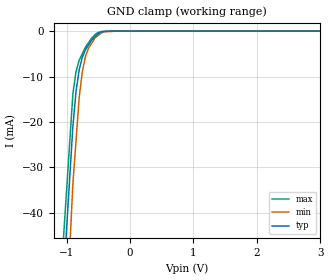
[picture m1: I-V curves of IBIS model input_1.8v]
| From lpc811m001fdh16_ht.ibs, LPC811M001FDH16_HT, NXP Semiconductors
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[Model] input_1.8v
Model_type Input
Vinl = 540.000mV
Vinh = 1.26000V
C_comp 909.000fF 904.000fF 914.000fF
| variable typ   min   max
[Voltage Range] 1.80000V 1.65000V 1.95000V
[POWER Clamp Reference] 1.80000V 1.65000V 1.95000V
[GND Clamp Reference] 0.00000V 0.00000V 0.00000V
[Temperature Range]   25   105   -40
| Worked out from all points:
|   GND clamp passes 1 mA (typ) near -0.53 V on its own axis
[GND Clamp]
-1.8V     -226.1mA   -292.9mA   -207.1mA
-900mV    -20.98mA   -33.67mA   -13.8mA
-850mV    -13.28mA   -24.09mA   -8.911mA
-800mV    -8.483mA   -14.52mA   -6.412mA
-750mV    -5.729mA   -8.869mA   -4.946mA
-700mV    -4.056mA   -5.491mA   -3.479mA
-650mV    -2.988mA   -3.674mA   -2.487mA
-550mV    -1.226mA   -1.484mA   -758.6uA
-500mV    -532.9uA   -938.4uA   -295.9uA
-400mV    -46.91uA   -141uA     -71.69uA
-200mV    -8.97uA    -9.8uA     -21.03uA
3.6V      0A         0A         0A
[POWER Clamp]
-1.8V     0A         0A         0A
3.6V      0A         0A         0A
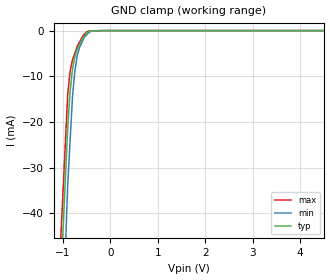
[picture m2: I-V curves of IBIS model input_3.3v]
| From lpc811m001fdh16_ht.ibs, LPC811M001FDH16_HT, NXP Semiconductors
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[Model] input_3.3v
Model_type Input
Vinl = 990.000mV
Vinh = 2.31000V
C_comp 909.000fF 904.000fF 914.000fF
| variable typ   min   max
[Voltage Range] 3.30000V 3.00000V 3.60000V
[POWER Clamp Reference] 3.30000V 3.00000V 3.60000V
[GND Clamp Reference] 0.00000V 0.00000V 0.00000V
[Temperature Range]   25   105   -40
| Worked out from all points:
|   GND clamp passes 1 mA (typ) near -0.53 V on its own axis
[GND Clamp]
-3.3V     -567.9mA   -725mA     -529.3mA
-900mV    -20.98mA   -33.67mA   -13.8mA
-850mV    -13.28mA   -24.09mA   -8.911mA
-800mV    -8.483mA   -14.52mA   -6.412mA
-750mV    -5.729mA   -8.869mA   -4.946mA
-700mV    -4.056mA   -5.491mA   -3.479mA
-650mV    -2.988mA   -3.674mA   -2.487mA
-550mV    -1.226mA   -1.484mA   -758.6uA
-500mV    -532.9uA   -938.4uA   -295.9uA
-400mV    -46.91uA   -141uA     -71.69uA
-200mV    -8.97uA    -9.8uA     -21.03uA
6.6V      0A         0A         0A
[POWER Clamp]
-3.3V     0A         0A         0A
6.6V      0A         0A         0A
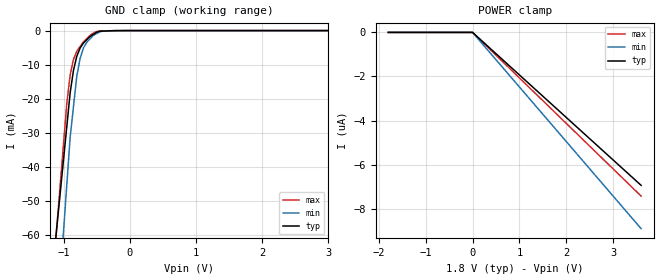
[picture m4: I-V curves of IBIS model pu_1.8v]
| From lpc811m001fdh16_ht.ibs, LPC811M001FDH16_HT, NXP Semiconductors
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[Model] pu_1.8v
Model_type Input
Vinl = 540.000mV
Vinh = 1.26000V
C_comp 909.000fF 904.000fF 914.000fF
| variable typ   min   max
[Voltage Range] 1.80000V 1.65000V 1.95000V
[POWER Clamp Reference] 1.80000V 1.65000V 1.95000V
[GND Clamp Reference] 0.00000V 0.00000V 0.00000V
[Temperature Range]   25   105   -40
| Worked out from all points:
|   GND clamp passes 1 mA (typ) near -0.54 V on its own axis
[GND Clamp]
-1.8V     -194.6mA   -279.4mA   -224.6mA
-950mV    -28.04mA   -45.07mA   -21.27mA
-900mV    -18.25mA   -31.28mA   -13mA
-850mV    -11.68mA   -22.35mA   -8.425mA
-800mV    -7.541mA   -13.41mA   -6.076mA
-750mV    -5.144mA   -8.205mA   -4.681mA
-700mV    -3.664mA   -5.125mA   -3.287mA
-650mV    -2.706mA   -3.458mA   -2.35mA
-550mV    -1.121mA   -1.408mA   -717.3uA
-400mV    -147.2uA   -139.2uA   -68.5uA
-200mV    -21.15uA   -18.17uA   -21.06uA
3.6V      0A         0A         0A
[POWER Clamp]
-1.8V     0A         0A         0A
0V        0A         0A         0A
3.6V      -6.941uA   -8.906uA   -7.427uA
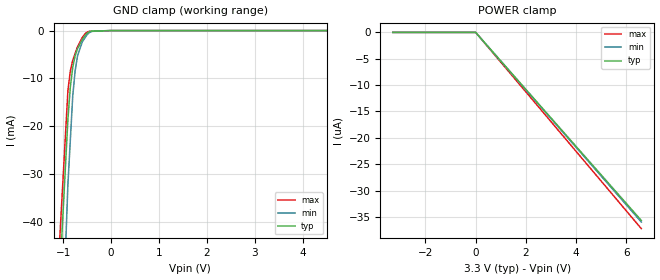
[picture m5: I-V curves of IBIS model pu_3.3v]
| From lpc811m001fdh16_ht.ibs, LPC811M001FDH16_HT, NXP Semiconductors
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[Model] pu_3.3v
Model_type Input
Vinl = 990.000mV
Vinh = 2.31000V
C_comp 909.000fF 904.000fF 914.000fF
| variable typ   min   max
[Voltage Range] 3.30000V 3.00000V 3.60000V
[POWER Clamp Reference] 3.30000V 3.00000V 3.60000V
[GND Clamp Reference] 0.00000V 0.00000V 0.00000V
[Temperature Range]   25   105   -40
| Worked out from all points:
|   GND clamp passes 1 mA (typ) near -0.54 V on its own axis
[GND Clamp]
-3.3V     -481.7mA   -686.3mA   -449mA
-900mV    -18.53mA   -32.17mA   -12.56mA
-850mV    -11.85mA   -22.98mA   -8.473mA
-800mV    -7.74mA    -13.78mA   -6.254mA
-750mV    -5.325mA   -8.465mA   -4.829mA
-700mV    -3.812mA   -5.309mA   -3.403mA
-600mV    -1.827mA   -2.349mA   -1.457mA
-550mV    -1.183mA   -1.595mA   -748.6uA
-500mV    -537.7uA   -841.1uA   -319uA
-400mV    -100.7uA   -173uA     -124uA
0V        0A         0A         0A
6.6V      0A         0A         0A
[POWER Clamp]
-3.3V     0A         0A         0A
0V        0A         0A         0A
6.6V      -35.67uA   -35.96uA   -37.22uA
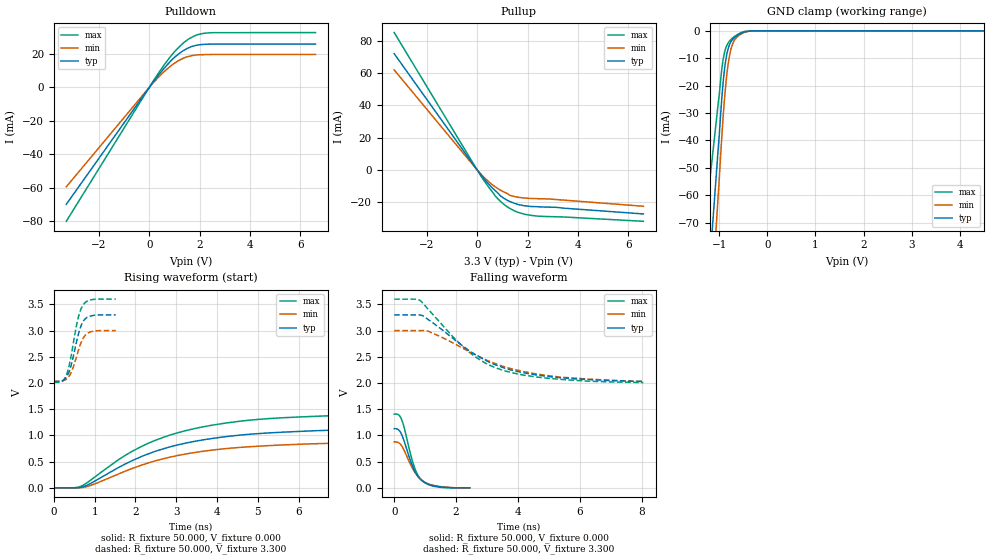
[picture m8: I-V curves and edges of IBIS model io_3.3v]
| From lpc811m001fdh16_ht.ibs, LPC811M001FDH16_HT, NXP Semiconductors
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[Model]   io_3.3v
Model_type I/O
Vinl=7.500E-01
Vinh=2.310E+00
Vref=0.000E+00
Rref=1.000E+06
Cref=2.000E-11
Vmeas=1.650E+00
C_comp   6.740E-13   6.620E-13   6.860E-13
[Voltage Range]   3.300E+00   3.000E+00   3.600E+00
[POWER Clamp Reference]   3.300E+00   3.000E+00   3.600E+00
[GND Clamp Reference]   0.000E+00   0.000E+00   0.000E+00
[Pullup Reference]   3.300E+00   3.000E+00   3.600E+00
[Pulldown Reference]   0.000E+00   0.000E+00   0.000E+00
[Temperature Range]   25   105   -40
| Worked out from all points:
|   slope of the pulldown table from 0 to 0.495 V, typ, clamps not added: 51.1 ohm
|   slope of the pullup table from 0 to 0.495 V, typ, clamps not added: 52.8 ohm
|   GND clamp passes 1 mA (typ) near -0.56 V on its own axis
|   rising waveform, R_fixture 50.000, V_fixture 0.000: 20-80 % time 2.35ns typ, 2.39ns min, 2.3ns max; typ from 0 V to 1.13 V
|   falling waveform, R_fixture 50.000, V_fixture 0.000: 20-80 % time 446ps typ, 505ps min, 399ps max; typ from 1.13 V to 0 V
|   rising waveform, R_fixture 50.000, V_fixture 3.300: 20-80 % time 242ps typ, 251ps min, 237ps max; typ from 2.03 V to 3.3 V
|   falling waveform, R_fixture 50.000, V_fixture 3.300: 20-80 % time 2.09ns typ, 2.37ns min, 1.84ns max; typ from 3.3 V to 2.03 V
[GND Clamp]
-3.3V     -588.5mA   -700.7mA   -393.5mA
-1.02V    -42.37mA   -59.29mA   -26.07mA
-1V       -37.98mA   -53.93mA   -23.34mA
-960mV    -27.56mA   -42.13mA   -15.89mA
-920mV    -18.87mA   -31.47mA   -10.48mA
-880mV    -12.49mA   -22.52mA   -7.138mA
-820mV    -6.819mA   -12.68mA   -4.563mA
-760mV    -4.057mA   -6.887mA   -3.228mA
-700mV    -2.719mA   -3.87mA    -2.258mA
-560mV    -996.8uA   -1.297mA   -753.3uA
-280mV    0A         0A         0A
6.6V      0A         0A         0A
[POWER Clamp]
-3.3V     0A         0A         0A
6.6V      0A         0A         0A
[Pullup]
-3.3V     72.06mA    62.01mA    85.16mA
80mV      -1.647mA   -1.409mA   -2.034mA
400mV     -7.816mA   -6.431mA   -9.395mA
720mV     -12.83mA   -10.45mA   -16.17mA
920mV     -15.95mA   -12.45mA   -19.35mA
1.1V      -17.89mA   -13.87mA   -21.72mA
1.3V      -19.5mA    -15.64mA   -23.77mA
1.56V     -21.01mA   -16.65mA   -25.83mA
2.2V      -22.62mA   -17.62mA   -28.18mA
3.16V     -23.1mA    -18.29mA   -28.93mA
6.6V      -27.18mA   -22.42mA   -31.73mA
[Pulldown]
-3.3V     -69.88mA   -59.44mA   -80.02mA
160mV     3.31mA     2.772mA    3.836mA
580mV     11.24mA    9.263mA    13.18mA
840mV     15.57mA    12.61mA    18.32mA
1.04V     18.4mA     14.81mA    21.92mA
1.38V     22.17mA    17.55mA    26.83mA
1.58V     23.72mA    18.54mA    29mA
1.86V     25.05mA    19.3mA     31.09mA
2.26V     25.7mA     19.55mA    32.39mA
6.6V      25.81mA    19.62mA    32.68mA
[Rising Waveform]
R_fixture = 50.000
V_fixture = 0.000
V_fixture_min = 0.000
V_fixture_max = 0.000
|  time   V(typ)   V(min)   V(max)
0s        0V         0V         0V
660ps     9.804mV    3.652mV    29.06mV
920ps     91.74mV    50.39mV    156.8mV
1.62ns    401.8mV    275.4mV    554.5mV
2.16ns    601mV      435.3mV    793.7mV
2.86ns    783.9mV    587.4mV    1.009V
3.64ns    912.4mV    695.5mV    1.161V
4.54ns    1.004V     770.2mV    1.269V
5.5ns     1.057V     814.1mV    1.332V
9.16ns    1.13V      878mV      1.408V
[Falling Waveform]
R_fixture = 50.000
V_fixture = 0.000
V_fixture_min = 0.000
V_fixture_max = 0.000
|  time   V(typ)   V(min)   V(max)
0s        1.13V      878mV      1.408V
140ps     1.107V     862.2mV    1.393V
240ps     1.019V     803.4mV    1.304V
340ps     859.6mV    692.1mV    1.11V
620ps     378.3mV    343.5mV    452.4mV
740ps     244.3mV    237.9mV    270.6mV
880ps     144.9mV    151.8mV    152.8mV
1.1ns     69.19mV    76.27mV    66.24mV
1.36ns    28.86mV    37.81mV    21.61mV
2.44ns    0V         0V         0V
[Rising Waveform]
R_fixture = 50.000
V_fixture = 3.300
V_fixture_min = 3.000
V_fixture_max = 3.600
|  time   V(typ)   V(min)   V(max)
0s        2.03V      2.031V     2.01V
200ps     2.043V     2.037V     2.033V
320ps     2.124V     2.081V     2.175V
420ps     2.326V     2.193V     2.502V
580ps     2.863V     2.565V     3.185V
640ps     3.032V     2.711V     3.358V
720ps     3.176V     2.854V     3.492V
800ps     3.244V     2.934V     3.553V
920ps     3.281V     2.98V      3.588V
1.52ns    3.3V       3V         3.6V
[Falling Waveform]
R_fixture = 50.000
V_fixture = 3.300
V_fixture_min = 3.000
V_fixture_max = 3.600
|  time   V(typ)   V(min)   V(max)
0s        3.3V       3V         3.6V
820ps     3.299V     3V         3.582V
1.08ns    3.219V     2.994V     3.419V
1.92ns    2.842V     2.758V     2.868V
2.38ns    2.636V     2.614V     2.609V
2.94ns    2.438V     2.451V     2.383V
3.46ns    2.308V     2.329V     2.253V
4.16ns    2.198V     2.222V     2.154V
5.28ns    2.107V     2.12V      2.075V
8.06ns    2.03V      2.031V     2.01V
[Ramp]
dV/dt_r   6.7806E-01/2.3543E-09   5.2641E-01/2.3841E-09   8.4375E-01/2.2977E-09
dV/dt_f   7.6177E-01/2.0912E-09   5.8122E-01/2.3663E-09   9.5373E-01/1.8410E-09
R_load = 50
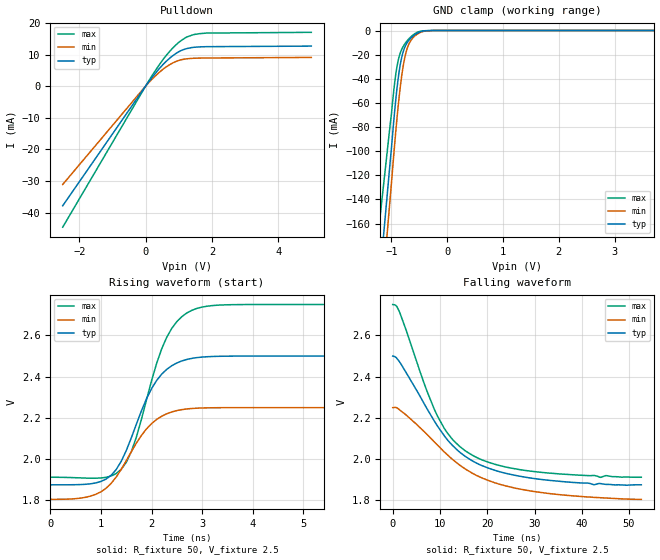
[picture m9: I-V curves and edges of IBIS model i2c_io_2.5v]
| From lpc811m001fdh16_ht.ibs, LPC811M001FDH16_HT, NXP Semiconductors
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[Model]   i2c_io_2.5v
Model_type I/O_open_drain
Vinl=7.500E-01
Vinh=1.750E+00
Vref=2.500E+00
Rref=1.000E+03
Cref=0.000E+00
Vmeas=1.250E+00
C_comp   1.060E-12   9.990E-13   1.120E-12
[Voltage Range]   2.500E+00   2.250E+00   2.750E+00
[POWER Clamp Reference]   2.500E+00   2.250E+00   2.750E+00
[GND Clamp Reference]   0.000E+00   0.000E+00   0.000E+00
[Pullup Reference]   2.500E+00   2.250E+00   2.750E+00
[Pulldown Reference]   0.000E+00   0.000E+00   0.000E+00
[Temperature Range]   25   105   -40
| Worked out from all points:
|   slope of the pulldown table from 0 to 0.375 V, typ, clamps not added: 74 ohm
|   GND clamp passes 1 mA (typ) near -0.48 V on its own axis
|   rising waveform, R_fixture 50, V_fixture 2.5: 20-80 % time 662ps typ, 716ps min, 623ps max; typ from 1.88 V to 2.5 V
|   falling waveform, R_fixture 50, V_fixture 2.5: 20-80 % time 12.3ns typ, 15.1ns min, 9.87ns max; typ from 2.5 V to 1.88 V
[GND Clamp]
-2.5V     -871.4mA   -953mA     -702mA
-1.02V    -107.3mA   -137.3mA   -76.75mA
-940mV    -65.71mA   -92.99mA   -42.42mA
-900mV    -47.69mA   -72.39mA   -29.64mA
-860mV    -33.38mA   -54.17mA   -21.27mA
-800mV    -19.22mA   -32.5mA    -14.12mA
-760mV    -13.76mA   -22.26mA   -11.09mA
-700mV    -8.816mA   -12.56mA   -7.482mA
-640mV    -5.775mA   -7.529mA   -4.759mA
-540mV    -2.236mA   -3.07mA    -1.531mA
-260mV    -4.949uA   -10.54uA   -1.512uA
5V        0A         0A         0A
[Pulldown]
-2.5V     -37.8mA    -31.08mA   -44.56mA
180mV     2.565mA    2.056mA    3.083mA
620mV     7.838mA    6.082mA    9.666mA
820mV     9.63mA     7.337mA    12.05mA
1.04V     11.1mA     8.257mA    14.16mA
1.24V     11.87mA    8.644mA    15.52mA
1.44V     12.27mA    8.811mA    16.26mA
1.84V     12.48mA    8.899mA    16.78mA
5V        12.66mA    9.081mA    17.01mA
[Rising Waveform]
R_fixture = 50
V_fixture = 2.5
V_fixture_min = 2.25
V_fixture_max = 2.75
0s        1.876V     1.805V     1.912V
900ps     1.885V     1.83V      1.908V
1.2ns     1.922V     1.882V     1.918V
1.4ns     1.989V     1.95V      1.951V
1.7ns     2.17V      2.078V     2.107V
2ns       2.342V     2.172V     2.381V
2.3ns     2.436V     2.22V      2.591V
2.5ns     2.467V     2.236V     2.667V
2.8ns     2.489V     2.246V     2.722V
7.6ns     2.5V       2.25V      2.75V
[Falling Waveform]
R_fixture = 50
V_fixture = 2.5
V_fixture_min = 2.25
V_fixture_max = 2.75
0s        2.5V       2.25V      2.75V
1.4ns     2.473V     2.241V     2.716V
6.7ns     2.267V     2.133V     2.364V
9.5ns     2.16V      2.068V     2.208V
12.3ns    2.075V     2.006V     2.106V
15.4ns    2.013V     1.952V     2.04V
20.4ns    1.955V     1.895V     1.984V
28.6ns    1.911V     1.848V     1.944V
42.6ns    1.876V     1.815V     1.921V
52.6ns    1.876V     1.805V     1.912V
[Ramp]
dV/dt_r   3.7455E-01/6.5770E-10   2.6675E-01/7.1020E-10   5.0254E-01/6.1810E-10
dV/dt_f   3.7455E-01/1.2195E-08   2.6675E-01/1.5100E-08   5.0254E-01/9.8059E-09
R_load = 50
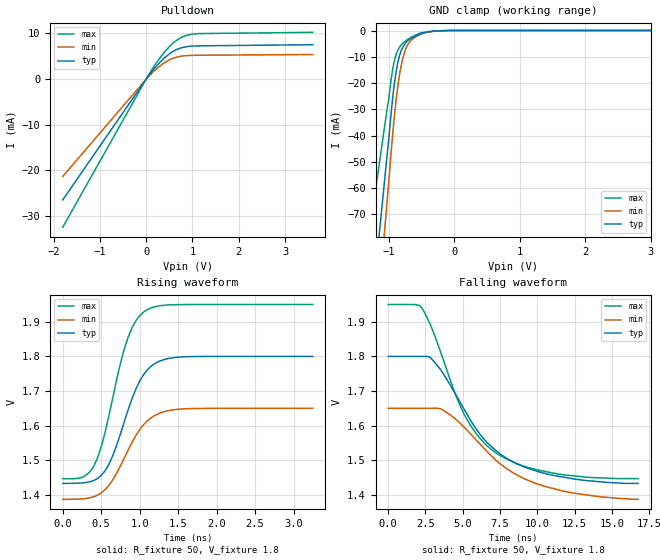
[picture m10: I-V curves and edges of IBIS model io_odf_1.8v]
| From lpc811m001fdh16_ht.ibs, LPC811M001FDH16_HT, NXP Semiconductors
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[Model]   io_odf_1.8v
Model_type I/O_open_drain
Vinl=5.400E-01
Vinh=1.260E+00
Vref=1.800E+00
Rref=1.000E+03
Cref=2.000E-11
Vmeas=9.000E-01
C_comp   6.740E-13   6.620E-13   6.860E-13
[Voltage Range]   1.800E+00   1.650E+00   1.950E+00
[POWER Clamp Reference]   1.800E+00   1.650E+00   1.950E+00
[GND Clamp Reference]   0.000E+00   0.000E+00   0.000E+00
[Pullup Reference]   1.800E+00   1.650E+00   1.950E+00
[Pulldown Reference]   0.000E+00   0.000E+00   0.000E+00
[Temperature Range]   25   105   -40
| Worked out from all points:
|   slope of the pulldown table from 0 to 0.27 V, typ, clamps not added: 80.1 ohm
|   GND clamp passes 1 mA (typ) near -0.48 V on its own axis
|   rising waveform, R_fixture 50, V_fixture 1.8: 20-80 % time 359ps typ, 393ps min, 330ps max; typ from 1.43 V to 1.8 V
|   falling waveform, R_fixture 50, V_fixture 1.8: 20-80 % time 3.86ns typ, 4.46ns min, 3.28ns max; typ from 1.8 V to 1.43 V
[GND Clamp]
-1.8V     -242.4mA   -294.1mA   -165mA
-1.02V    -46.29mA   -63.69mA   -29.16mA
-960mV    -30.77mA   -45.66mA   -18.16mA
-920mV    -21.6mA    -34.49mA   -12.29mA
-880mV    -14.71mA   -25.13mA   -8.671mA
-840mV    -10.06mA   -17.73mA   -6.556mA
-800mV    -7.156mA   -12.24mA   -5.232mA
-760mV    -5.384mA   -8.427mA   -4.336mA
-660mV    -3.035mA   -3.787mA   -2.632mA
-460mV    -820.3uA   -973.5uA   -679.2uA
-240mV    -118.6uA   -128uA     -99.16uA
3.6V      0A         0A         0A
[Pulldown]
-1.8V     -26.43mA   -21.3mA    -32.41mA
0V        0A         0A         0A
140mV     1.894mA    1.498mA    2.358mA
320mV     3.92mA     3.046mA    4.957mA
500mV     5.527mA    4.203mA    7.12mA
600mV     6.186mA    4.638mA    8.066mA
740mV     6.795mA    4.997mA    9.018mA
880mV     7.12mA     5.157mA    9.607mA
1.14V     7.295mA    5.238mA    9.978mA
3.6V      7.545mA    5.395mA    10.26mA
[Rising Waveform]
R_fixture = 50
V_fixture = 1.8
V_fixture_min = 1.65
V_fixture_max = 1.95
0s        1.433V     1.387V     1.447V
250ps     1.435V     1.388V     1.451V
400ps     1.441V     1.394V     1.482V
500ps     1.456V     1.406V     1.539V
600ps     1.489V     1.428V     1.629V
800ps     1.612V     1.507V     1.822V
900ps     1.678V     1.552V     1.883V
1.05ns    1.747V     1.603V     1.928V
1.45ns    1.797V     1.646V     1.949V
3.25ns    1.8V       1.65V      1.95V
[Falling Waveform]
R_fixture = 50
V_fixture = 1.8
V_fixture_min = 1.65
V_fixture_max = 1.95
0s        1.8V       1.65V      1.95V
2.25ns    1.8V       1.65V      1.941V
2.8ns     1.797V     1.65V      1.895V
3.25ns    1.777V     1.65V      1.845V
5.1ns     1.647V     1.595V     1.632V
6.1ns     1.578V     1.55V      1.566V
7.2ns     1.529V     1.501V     1.522V
8.6ns     1.49V      1.458V     1.491V
10.5ns    1.462V     1.425V     1.468V
16.75ns   1.433V     1.387V     1.447V
[Ramp]
dV/dt_r   2.2008E-01/3.5720E-10   1.5771E-01/3.9130E-10   3.0181E-01/3.2830E-10
dV/dt_f   2.2008E-01/3.8135E-09   1.5771E-01/4.4437E-09   3.0181E-01/3.2768E-09
R_load = 50
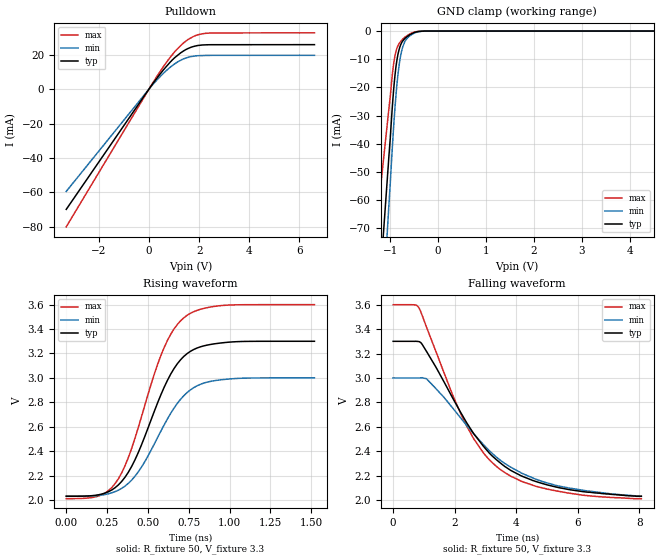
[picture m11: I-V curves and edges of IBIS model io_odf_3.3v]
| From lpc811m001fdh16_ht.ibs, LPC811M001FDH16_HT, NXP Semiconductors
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[Model]   io_odf_3.3v
Model_type I/O_open_drain
Vinl=7.500E-01
Vinh=2.310E+00
Vref=3.300E+00
Rref=1.000E+03
Cref=2.000E-11
Vmeas=1.650E+00
C_comp   6.740E-13   6.620E-13   6.860E-13
[Voltage Range]   3.300E+00   3.000E+00   3.600E+00
[POWER Clamp Reference]   3.300E+00   3.000E+00   3.600E+00
[GND Clamp Reference]   0.000E+00   0.000E+00   0.000E+00
[Pullup Reference]   3.300E+00   3.000E+00   3.600E+00
[Pulldown Reference]   0.000E+00   0.000E+00   0.000E+00
[Temperature Range]   25   105   -40
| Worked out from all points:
|   slope of the pulldown table from 0 to 0.495 V, typ, clamps not added: 51.1 ohm
|   GND clamp passes 1 mA (typ) near -0.56 V on its own axis
|   rising waveform, R_fixture 50, V_fixture 3.3: 20-80 % time 242ps typ, 251ps min, 237ps max; typ from 2.03 V to 3.3 V
|   falling waveform, R_fixture 50, V_fixture 3.3: 20-80 % time 2.09ns typ, 2.37ns min, 1.84ns max; typ from 3.3 V to 2.03 V
[GND Clamp]
-3.3V     -588.5mA   -700.7mA   -393.5mA
-1.02V    -42.37mA   -59.29mA   -26.07mA
-1V       -37.98mA   -53.93mA   -23.34mA
-960mV    -27.56mA   -42.13mA   -15.89mA
-920mV    -18.87mA   -31.47mA   -10.48mA
-880mV    -12.49mA   -22.52mA   -7.138mA
-820mV    -6.819mA   -12.68mA   -4.563mA
-760mV    -4.057mA   -6.887mA   -3.228mA
-700mV    -2.719mA   -3.87mA    -2.258mA
-560mV    -996.8uA   -1.297mA   -753.3uA
-280mV    0A         0A         0A
6.6V      0A         0A         0A
[Pulldown]
-3.3V     -69.88mA   -59.44mA   -80.02mA
160mV     3.31mA     2.772mA    3.836mA
580mV     11.24mA    9.263mA    13.18mA
840mV     15.57mA    12.61mA    18.32mA
1.04V     18.4mA     14.81mA    21.92mA
1.38V     22.17mA    17.55mA    26.83mA
1.58V     23.72mA    18.54mA    29mA
1.86V     25.05mA    19.3mA     31.09mA
2.26V     25.7mA     19.55mA    32.39mA
6.6V      25.81mA    19.62mA    32.68mA
[Rising Waveform]
R_fixture = 50
V_fixture = 3.3
V_fixture_min = 3
V_fixture_max = 3.6
0s        2.03V      2.031V     2.01V
200ps     2.043V     2.037V     2.033V
320ps     2.124V     2.081V     2.175V
420ps     2.326V     2.193V     2.502V
580ps     2.863V     2.565V     3.185V
640ps     3.032V     2.71V      3.358V
720ps     3.176V     2.854V     3.492V
800ps     3.244V     2.934V     3.553V
920ps     3.282V     2.98V      3.588V
1.52ns    3.3V       3V         3.6V
[Falling Waveform]
R_fixture = 50
V_fixture = 3.3
V_fixture_min = 3
V_fixture_max = 3.6
0s        3.3V       3V         3.6V
820ps     3.298V     3V         3.582V
1.08ns    3.219V     2.994V     3.419V
1.92ns    2.842V     2.758V     2.868V
2.38ns    2.636V     2.614V     2.609V
2.94ns    2.438V     2.452V     2.383V
3.46ns    2.307V     2.33V      2.253V
4.16ns    2.198V     2.222V     2.154V
5.28ns    2.107V     2.12V      2.075V
8.06ns    2.03V      2.031V     2.01V
[Ramp]
dV/dt_r   7.6177E-01/2.4180E-10   5.8122E-01/2.5030E-10   9.5373E-01/2.3600E-10
dV/dt_f   7.6177E-01/2.0912E-09   5.8122E-01/2.3663E-09   9.5373E-01/1.8410E-09
R_load = 50
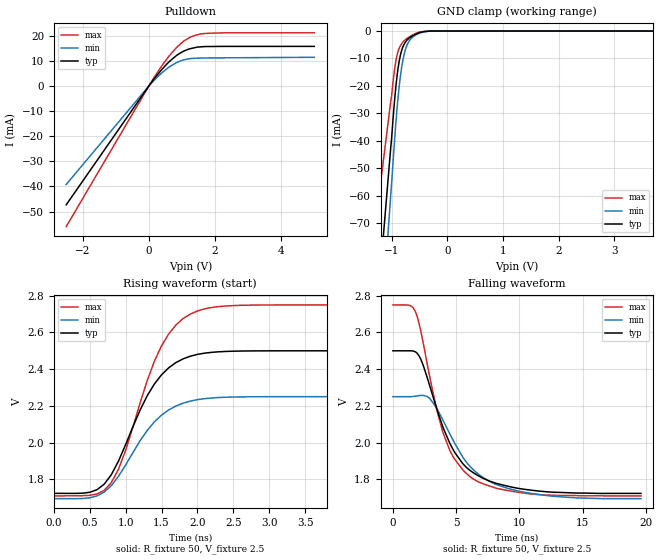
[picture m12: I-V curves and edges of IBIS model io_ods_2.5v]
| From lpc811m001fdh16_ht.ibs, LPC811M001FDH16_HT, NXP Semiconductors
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[Model]   io_ods_2.5v
Model_type I/O_open_drain
Vinl=7.500E-01
Vinh=1.750E+00
Vref=2.500E+00
Rref=1.000E+03
Cref=2.000E-11
Vmeas=1.250E+00
C_comp   8.440E-13   8.280E-13   8.600E-13
[Voltage Range]   2.500E+00   2.250E+00   2.750E+00
[POWER Clamp Reference]   2.500E+00   2.250E+00   2.750E+00
[GND Clamp Reference]   0.000E+00   0.000E+00   0.000E+00
[Pullup Reference]   2.500E+00   2.250E+00   2.750E+00
[Pulldown Reference]   0.000E+00   0.000E+00   0.000E+00
[Temperature Range]   25   105   -40
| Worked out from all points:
|   slope of the pulldown table from 0 to 0.375 V, typ, clamps not added: 59.7 ohm
|   GND clamp passes 1 mA (typ) near -0.55 V on its own axis
|   rising waveform, R_fixture 50, V_fixture 2.5: 20-80 % time 578ps typ, 591ps min, 561ps max; typ from 1.72 V to 2.5 V
|   falling waveform, R_fixture 50, V_fixture 2.5: 20-80 % time 2.86ns typ, 3.39ns min, 2.42ns max; typ from 2.5 V to 1.72 V
[GND Clamp]
-2.5V     -404.1mA   -486.6mA   -268mA
-1.02V    -43.34mA   -60.87mA   -26.26mA
-1V       -38.9mA    -55.38mA   -23.5mA
-960mV    -28.26mA   -43.32mA   -15.92mA
-920mV    -19.44mA   -32.41mA   -10.46mA
-880mV    -12.92mA   -23.27mA   -7.117mA
-820mV    -7.05mA    -13.2mA    -4.611mA
-780mV    -4.988mA   -8.816mA   -3.648mA
-720mV    -3.227mA   -4.893mA   -2.614mA
-580mV    -1.266mA   -1.615mA   -979uA
-300mV    0A         0A         0A
5V        0A         0A         0A
[Pulldown]
-2.5V     -47.31mA   -39.21mA   -55.99mA
120mV     2.157mA    1.744mA    2.601mA
580mV     9.212mA    7.217mA    11.4mA
840mV     12.14mA    9.295mA    15.36mA
1.04V     13.78mA    10.32mA    17.7mA
1.36V     15.14mA    10.99mA    19.99mA
1.7V      15.67mA    11.12mA    20.87mA
5V        15.74mA    11.4mA     21.14mA
[Rising Waveform]
R_fixture = 50
V_fixture = 2.5
V_fixture_min = 2.25
V_fixture_max = 2.75
0s        1.723V     1.694V     1.709V
500ps     1.729V     1.699V     1.713V
800ps     1.824V     1.765V     1.781V
1ns       1.989V     1.878V     1.958V
1.3ns     2.255V     2.066V     2.337V
1.5ns     2.369V     2.15V      2.527V
1.7ns     2.436V     2.199V     2.641V
2ns       2.48V      2.234V     2.717V
2.7ns     2.499V     2.249V     2.749V
6.8ns     2.5V       2.25V      2.75V
[Falling Waveform]
R_fixture = 50
V_fixture = 2.5
V_fixture_min = 2.25
V_fixture_max = 2.75
0s        2.5V       2.25V      2.75V
1.8ns     2.494V     2.253V     2.71V
2.3ns     2.438V     2.257V     2.575V
2.9ns     2.311V     2.241V     2.361V
4ns       2.076V     2.116V     2.046V
4.9ns     1.945V     1.994V     1.907V
6.1ns     1.848V     1.869V     1.814V
7.6ns     1.791V     1.79V      1.764V
10.3ns    1.746V     1.731V     1.725V
19.6ns    1.723V     1.694V     1.709V
[Ramp]
dV/dt_r   4.6607E-01/5.7220E-10   3.3343E-01/5.8610E-10   6.2439E-01/5.5610E-10
dV/dt_f   4.6607E-01/2.8578E-09   3.3343E-01/3.3809E-09   6.2439E-01/2.4125E-09
R_load = 50
